VERSION 5.8 ;
BUSBITCHARS "[]" ;
DIVIDERCHAR "/" ;
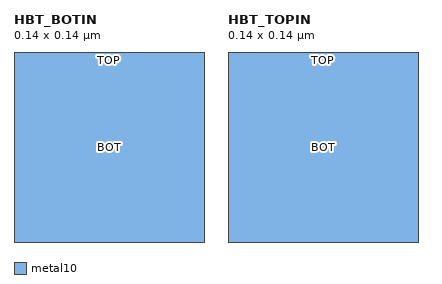
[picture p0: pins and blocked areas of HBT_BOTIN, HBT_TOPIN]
MACRO HBT_BOTIN
  CLASS COVER ;
  ORIGIN 0 0 ;
  FOREIGN HBT_BOTIN 0 0 ;
  SIZE 0.14 BY 0.14 ;
  SYMMETRY X Y ;
  PIN BOT
    DIRECTION INPUT ;
    USE SIGNAL ;
    PORT
      LAYER metal10 ;
      RECT 0 0 0.14 0.14 ;
    END
  END BOT
  PIN TOP
    DIRECTION OUTPUT ;
    USE SIGNAL ;
    PORT
      LAYER metal10 ;
      RECT 0 0 0.14 0.14 ;
    END
  END TOP
END HBT_BOTIN
MACRO HBT_TOPIN
  CLASS COVER ;
  ORIGIN 0 0 ;
  FOREIGN HBT_TOPIN 0 0 ;
  SIZE 0.14 BY 0.14 ;
  SYMMETRY X Y ;
  PIN TOP
    DIRECTION INPUT ;
    USE SIGNAL ;
    PORT
      LAYER metal10 ;
      RECT 0 0 0.14 0.14 ;
    END
  END TOP
  PIN BOT
    DIRECTION OUTPUT ;
    USE SIGNAL ;
    PORT
      LAYER metal10 ;
      RECT 0 0 0.14 0.14 ;
    END
  END BOT
END HBT_TOPIN
END LIBRARY
